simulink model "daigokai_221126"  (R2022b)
settings: Solver=VariableStepAuto  StartTime=0.0  StopTime=40  RelTol=1e-3
PreLoadFcn:
  | Kp=1
  | Ki=1

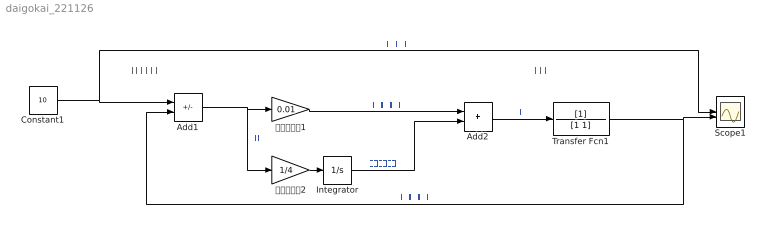
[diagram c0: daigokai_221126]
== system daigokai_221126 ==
  note: プログラム
  note: 乗り物
  Add1 : Sum  Inputs=+-
  Add2 : Sum
  Constant1 : Constant  Value=10
  Integrator : Integrator
  Scope1 : Scope  NumInputPorts=2
  Transfer Fcn1 : TransferFcn  Denominator=[1 1]
  比例ゲイン1 : Gain  Gain=0.01
  比例ゲイン2 : Gain  Gain=1/4
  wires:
  Transfer Fcn1/1 -> Add1/2, Scope1/2  "乗り物の速度"
  Add1/1 -> 比例ゲイン2/1, 比例ゲイン1/1  "偏差"
  比例ゲイン1/1 -> Add2/1  "比例項の出力"
  Constant1/1 -> Scope1/1, Add1/1  "ロボットの速度"
  比例ゲイン2/1 -> Integrator/1
  Add2/1 -> Transfer Fcn1/1  "力"
  Integrator/1 -> Add2/2  "積分項の出力"
